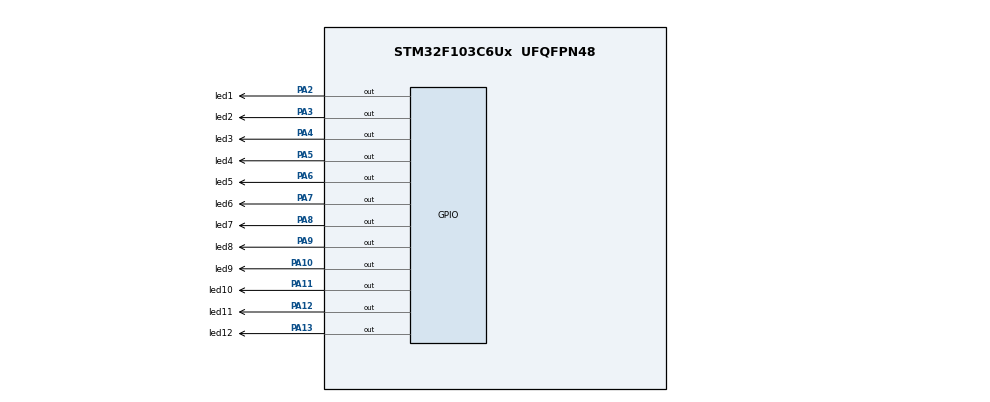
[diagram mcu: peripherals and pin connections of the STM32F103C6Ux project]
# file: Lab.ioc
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Mcu.Family=STM32F1
Mcu.Name=STM32F103C6Ux
Mcu.Package=UFQFPN48
NVIC.PriorityGroup=NVIC_PRIORITYGROUP_4
PA10.GPIO_Label=led9
PA10.Signal=GPIO_Output
PA11.GPIO_Label=led10
PA11.Signal=GPIO_Output
PA12.GPIO_Label=led11
PA12.Signal=GPIO_Output
PA13.GPIO_Label=led12
PA13.Signal=GPIO_Output
PA2.GPIO_Label=led1
PA2.Signal=GPIO_Output
PA3.GPIO_Label=led2
PA3.Signal=GPIO_Output
PA4.GPIO_Label=led3
PA4.Signal=GPIO_Output
PA5.GPIO_Label=led4
PA5.Signal=GPIO_Output
PA6.GPIO_Label=led5
PA6.Signal=GPIO_Output
PA7.GPIO_Label=led6
PA7.Signal=GPIO_Output
PA8.GPIO_Label=led7
PA8.Signal=GPIO_Output
PA9.GPIO_Label=led8
PA9.Signal=GPIO_Output
ProjectManager.HeapSize=0x200
ProjectManager.StackSize=0x400
ProjectManager.TargetToolchain=STM32CubeIDE
RCC.APB1Freq_Value=8000000
RCC.APB2Freq_Value=8000000
VP_SYS_VS_ND.Mode=No_Debug
board=custom

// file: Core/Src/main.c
/* USER CODE BEGIN Header */
/**
  ******************************************************************************
  * @file           : main.c
  * @brief          : Main program body
  ******************************************************************************
  * @attention
  *
  * <h2><center>&copy; Copyright (c) 2022 STMicroelectronics.
  * All rights reserved.</center></h2>
  *
  * This software component is licensed by ST under BSD 3-Clause license,
  * the "License"; You may not use this file except in compliance with the
  * License. You may obtain a copy of the License at:
  *                        opensource.org/licenses/BSD-3-Clause
  *
  ******************************************************************************
  */
/* USER CODE END Header */
#include "main.h"

void SystemClock_Config(void);
static void MX_GPIO_Init(void);

int main(void)
{

  /* MCU Configuration--------------------------------------------------------*/

  /* Reset of all peripherals, Initializes the Flash interface and the Systick. */
  HAL_Init();

  /* Configure the system clock */
  SystemClock_Config();

  /* Initialize all configured peripherals */
  MX_GPIO_Init();

  /* Infinite loop */
  /* USER CODE BEGIN WHILE */
  while (1)
  {
	  HAL_GPIO_WritePin (green1_GPIO_Port , green1_Pin, GPIO_PIN_RESET);
	  HAL_GPIO_WritePin (yellow1_GPIO_Port , yellow1_Pin, GPIO_PIN_RESET);
	  HAL_GPIO_WritePin (green2_GPIO_Port , green2_Pin, GPIO_PIN_SET); //Green 2 on
	  HAL_GPIO_WritePin (yellow2_GPIO_Port , yellow2_Pin, GPIO_PIN_RESET);
	  HAL_GPIO_WritePin (green3_GPIO_Port , green3_Pin, GPIO_PIN_RESET);
	  HAL_GPIO_WritePin (yellow3_GPIO_Port , yellow3_Pin, GPIO_PIN_RESET);
	  HAL_GPIO_WritePin (red2_GPIO_Port , red2_Pin, GPIO_PIN_RESET);
	  HAL_GPIO_WritePin (red4_GPIO_Port , red4_Pin, GPIO_PIN_RESET);
	  HAL_GPIO_WritePin (green4_GPIO_Port , green4_Pin, GPIO_PIN_SET); //Green4 on
	  HAL_GPIO_WritePin (yellow4_GPIO_Port , yellow4_Pin, GPIO_PIN_RESET);
	  HAL_GPIO_WritePin (red1_GPIO_Port , red1_Pin, GPIO_PIN_SET); //red 1 on
	  HAL_GPIO_WritePin (red3_GPIO_Port , red3_Pin, GPIO_PIN_SET); //red 3 on
	  display7SEG(3);
	  HAL_Delay(1000);
	  display7SEG(2);
	  HAL_Delay(1000);
	  display7SEG(1);
	  HAL_Delay(1000);

	  //Next state
	  HAL_GPIO_WritePin (green1_GPIO_Port , green1_Pin, GPIO_PIN_RESET);
	  HAL_GPIO_WritePin (yellow1_GPIO_Port , yellow1_Pin, GPIO_PIN_RESET); //YELLOW1
	  HAL_GPIO_WritePin (green2_GPIO_Port , green2_Pin, GPIO_PIN_RESET);
	  HAL_GPIO_WritePin (yellow2_GPIO_Port , yellow2_Pin, GPIO_PIN_SET); //yellow on
	  HAL_GPIO_WritePin (green3_GPIO_Port , green3_Pin, GPIO_PIN_RESET);
	  HAL_GPIO_WritePin (yellow3_GPIO_Port , yellow3_Pin, GPIO_PIN_RESET); //YELLOW3
	  HAL_GPIO_WritePin (red2_GPIO_Port , red2_Pin, GPIO_PIN_RESET);
	  HAL_GPIO_WritePin (red4_GPIO_Port , red4_Pin, GPIO_PIN_RESET);
	  HAL_GPIO_WritePin (green4_GPIO_Port , green4_Pin, GPIO_PIN_RESET);
	  HAL_GPIO_WritePin (yellow4_GPIO_Port , yellow4_Pin, GPIO_PIN_SET); // yellow on
	  HAL_GPIO_WritePin (red1_GPIO_Port , red1_Pin, GPIO_PIN_SET);
	  HAL_GPIO_WritePin (red3_GPIO_Port , red3_Pin, GPIO_PIN_SET);
	  display7SEG(2);
	  HAL_Delay(1000);
	  display7SEG(1);
	  HAL_Delay(1000);

	  //Next State
	  HAL_GPIO_WritePin (green1_GPIO_Port , green1_Pin, GPIO_PIN_SET); //green 1 on
	  HAL_GPIO_WritePin (yellow1_GPIO_Port , yellow1_Pin, GPIO_PIN_RESET);
	  HAL_GPIO_WritePin (green2_GPIO_Port , green2_Pin, GPIO_PIN_RESET);
	  HAL_GPIO_WritePin (yellow2_GPIO_Port , yellow2_Pin, GPIO_PIN_RESET);
	  HAL_GPIO_WritePin (green3_GPIO_Port , green3_Pin, GPIO_PIN_SET); // green 3 on
	  HAL_GPIO_WritePin (yellow3_GPIO_Port , yellow3_Pin, GPIO_PIN_RESET);
	  HAL_GPIO_WritePin (red2_GPIO_Port , red2_Pin, GPIO_PIN_SET); //red 2 on
	  HAL_GPIO_WritePin (red4_GPIO_Port , red4_Pin, GPIO_PIN_SET);// red 4 on
	  HAL_GPIO_WritePin (green4_GPIO_Port , green4_Pin, GPIO_PIN_RESET);
	  HAL_GPIO_WritePin (yellow4_GPIO_Port , yellow4_Pin, GPIO_PIN_RESET);
	  HAL_GPIO_WritePin (red1_GPIO_Port , red1_Pin, GPIO_PIN_RESET);
	  HAL_GPIO_WritePin (red3_GPIO_Port , red3_Pin, GPIO_PIN_RESET);
	  display7SEG(3);
	  HAL_Delay(1000);
	  display7SEG(2);
	  HAL_Delay(1000);
	  display7SEG(1);
	  HAL_Delay(1000);

	  //FINAL STATE
	  HAL_GPIO_WritePin (green1_GPIO_Port , green1_Pin, GPIO_PIN_RESET);
	  HAL_GPIO_WritePin (yellow1_GPIO_Port , yellow1_Pin, GPIO_PIN_SET); //yellow on
	  HAL_GPIO_WritePin (green2_GPIO_Port , green2_Pin, GPIO_PIN_RESET);
	  HAL_GPIO_WritePin (yellow2_GPIO_Port , yellow2_Pin, GPIO_PIN_RESET); //YELLOW2
	  HAL_GPIO_WritePin (green3_GPIO_Port , green3_Pin, GPIO_PIN_RESET);
	  HAL_GPIO_WritePin (yellow3_GPIO_Port , yellow3_Pin, GPIO_PIN_SET); //yellow on
	  HAL_GPIO_WritePin (red2_GPIO_Port , red2_Pin, GPIO_PIN_SET);
	  HAL_GPIO_WritePin (red4_GPIO_Port , red4_Pin, GPIO_PIN_SET);
	  HAL_GPIO_WritePin (green4_GPIO_Port , green4_Pin, GPIO_PIN_RESET);
	  HAL_GPIO_WritePin (yellow4_GPIO_Port , yellow4_Pin, GPIO_PIN_RESET); //YELLOW4
	  HAL_GPIO_WritePin (red1_GPIO_Port , red1_Pin, GPIO_PIN_RESET);
	  HAL_GPIO_WritePin (red3_GPIO_Port , red3_Pin, GPIO_PIN_RESET);
	  display7SEG(2);
	  HAL_Delay(1000);
	  display7SEG(1);
	  HAL_Delay(1000);

  }
  /* USER CODE END 3 */
}

void SystemClock_Config(void)
{
  RCC_OscInitTypeDef RCC_OscInitStruct = {0};
  RCC_ClkInitTypeDef RCC_ClkInitStruct = {0};

  /** Initializes the RCC Oscillators according to the specified parameters
  * in the RCC_OscInitTypeDef structure.
  */
  RCC_OscInitStruct.OscillatorType = RCC_OSCILLATORTYPE_HSI;
  RCC_OscInitStruct.HSIState = RCC_HSI_ON;
  RCC_OscInitStruct.HSICalibrationValue = RCC_HSICALIBRATION_DEFAULT;
  RCC_OscInitStruct.PLL.PLLState = RCC_PLL_NONE;
  if (HAL_RCC_OscConfig(&RCC_OscInitStruct) != HAL_OK)
  {
    Error_Handler();
  }
  /** Initializes the CPU, AHB and APB buses clocks
  */
  RCC_ClkInitStruct.ClockType = RCC_CLOCKTYPE_HCLK|RCC_CLOCKTYPE_SYSCLK
                              |RCC_CLOCKTYPE_PCLK1|RCC_CLOCKTYPE_PCLK2;
  RCC_ClkInitStruct.SYSCLKSource = RCC_SYSCLKSOURCE_HSI;
  RCC_ClkInitStruct.AHBCLKDivider = RCC_SYSCLK_DIV1;
  RCC_ClkInitStruct.APB1CLKDivider = RCC_HCLK_DIV1;
  RCC_ClkInitStruct.APB2CLKDivider = RCC_HCLK_DIV1;

  if (HAL_RCC_ClockConfig(&RCC_ClkInitStruct, FLASH_LATENCY_0) != HAL_OK)
  {
    Error_Handler();
  }
}

static void MX_GPIO_Init(void)
{
  GPIO_InitTypeDef GPIO_InitStruct = {0};

  /* GPIO Ports Clock Enable */
  __HAL_RCC_GPIOA_CLK_ENABLE();
  __HAL_RCC_GPIOB_CLK_ENABLE();

  /*Configure GPIO pin Output Level */
  HAL_GPIO_WritePin(GPIOA, red1_Pin|green1_Pin|yellow1_Pin|red2_Pin
                          |green2_Pin|yellow2_Pin|red3_Pin|green3_Pin
                          |yellow3_Pin|red4_Pin|green4_Pin|yellow4_Pin, GPIO_PIN_RESET);

  /*Configure GPIO pin Output Level */
  HAL_GPIO_WritePin(GPIOB, a_Pin|b_Pin|c_Pin|d_Pin
                          |e_Pin|f_Pin|g_Pin, GPIO_PIN_RESET);

  /*Configure GPIO pins : red1_Pin green1_Pin yellow1_Pin red2_Pin
                           green2_Pin yellow2_Pin red3_Pin green3_Pin
                           yellow3_Pin red4_Pin green4_Pin yellow4_Pin */
  GPIO_InitStruct.Pin = red1_Pin|green1_Pin|yellow1_Pin|red2_Pin
                          |green2_Pin|yellow2_Pin|red3_Pin|green3_Pin
                          |yellow3_Pin|red4_Pin|green4_Pin|yellow4_Pin;
  GPIO_InitStruct.Mode = GPIO_MODE_OUTPUT_PP;
  GPIO_InitStruct.Pull = GPIO_NOPULL;
  GPIO_InitStruct.Speed = GPIO_SPEED_FREQ_LOW;
  HAL_GPIO_Init(GPIOA, &GPIO_InitStruct);

  /*Configure GPIO pins : a_Pin b_Pin c_Pin d_Pin
                           e_Pin f_Pin g_Pin */
  GPIO_InitStruct.Pin = a_Pin|b_Pin|c_Pin|d_Pin
                          |e_Pin|f_Pin|g_Pin;
  GPIO_InitStruct.Mode = GPIO_MODE_OUTPUT_PP;
  GPIO_InitStruct.Pull = GPIO_NOPULL;
  GPIO_InitStruct.Speed = GPIO_SPEED_FREQ_LOW;
  HAL_GPIO_Init(GPIOB, &GPIO_InitStruct);

}

/* USER CODE BEGIN 4 */
void display7SEG(int counter){
	if(counter == 0){
		HAL_GPIO_WritePin (a_GPIO_Port, a_Pin, GPIO_PIN_RESET);
		HAL_GPIO_WritePin (b_GPIO_Port, b_Pin, GPIO_PIN_RESET);
		HAL_GPIO_WritePin (c_GPIO_Port, c_Pin, GPIO_PIN_RESET);
		HAL_GPIO_WritePin (d_GPIO_Port, d_Pin, GPIO_PIN_RESET);
		HAL_GPIO_WritePin (e_GPIO_Port, e_Pin, GPIO_PIN_RESET);
		HAL_GPIO_WritePin (f_GPIO_Port, f_Pin, GPIO_PIN_RESET);
		HAL_GPIO_WritePin (g_GPIO_Port, g_Pin, GPIO_PIN_SET);
	}
	else if(counter == 1){
		HAL_GPIO_WritePin (a_GPIO_Port, a_Pin, GPIO_PIN_SET);
		HAL_GPIO_WritePin (b_GPIO_Port, b_Pin, GPIO_PIN_RESET);
		HAL_GPIO_WritePin (c_GPIO_Port, c_Pin, GPIO_PIN_RESET);
		HAL_GPIO_WritePin (d_GPIO_Port, d_Pin, GPIO_PIN_SET);
		HAL_GPIO_WritePin (e_GPIO_Port, e_Pin, GPIO_PIN_SET);
		HAL_GPIO_WritePin (f_GPIO_Port, f_Pin, GPIO_PIN_SET);
		HAL_GPIO_WritePin (g_GPIO_Port, g_Pin, GPIO_PIN_SET);
	}
	else if (counter == 2){
		HAL_GPIO_WritePin (a_GPIO_Port, a_Pin, GPIO_PIN_RESET);
		HAL_GPIO_WritePin (b_GPIO_Port, b_Pin, GPIO_PIN_RESET);
		HAL_GPIO_WritePin (c_GPIO_Port, c_Pin, GPIO_PIN_SET);
		HAL_GPIO_WritePin (d_GPIO_Port, d_Pin, GPIO_PIN_RESET);
		HAL_GPIO_WritePin (e_GPIO_Port, e_Pin, GPIO_PIN_RESET);
		HAL_GPIO_WritePin (f_GPIO_Port, f_Pin, GPIO_PIN_SET);
		HAL_GPIO_WritePin (g_GPIO_Port, g_Pin, GPIO_PIN_RESET);
	}
	else if (counter == 3){
		HAL_GPIO_WritePin (a_GPIO_Port, a_Pin, GPIO_PIN_RESET);
		HAL_GPIO_WritePin (b_GPIO_Port, b_Pin, GPIO_PIN_RESET);
		HAL_GPIO_WritePin (c_GPIO_Port, c_Pin, GPIO_PIN_RESET);
		HAL_GPIO_WritePin (d_GPIO_Port, d_Pin, GPIO_PIN_RESET);
		HAL_GPIO_WritePin (e_GPIO_Port, e_Pin, GPIO_PIN_SET);
		HAL_GPIO_WritePin (f_GPIO_Port, f_Pin, GPIO_PIN_SET);
		HAL_GPIO_WritePin (g_GPIO_Port, g_Pin, GPIO_PIN_RESET);
	}
	else if (counter == 4){
		HAL_GPIO_WritePin (a_GPIO_Port, a_Pin, GPIO_PIN_SET);
		HAL_GPIO_WritePin (b_GPIO_Port, b_Pin, GPIO_PIN_RESET);
		HAL_GPIO_WritePin (c_GPIO_Port, c_Pin, GPIO_PIN_RESET);
		HAL_GPIO_WritePin (d_GPIO_Port, d_Pin, GPIO_PIN_SET);
		HAL_GPIO_WritePin (e_GPIO_Port, e_Pin, GPIO_PIN_SET);
		HAL_GPIO_WritePin (f_GPIO_Port, f_Pin, GPIO_PIN_RESET);
		HAL_GPIO_WritePin (g_GPIO_Port, g_Pin, GPIO_PIN_RESET);
	}
	else if (counter == 5){
		HAL_GPIO_WritePin (a_GPIO_Port, a_Pin, GPIO_PIN_RESET);
		HAL_GPIO_WritePin (b_GPIO_Port, b_Pin, GPIO_PIN_SET);
		HAL_GPIO_WritePin (c_GPIO_Port, c_Pin, GPIO_PIN_RESET);
		HAL_GPIO_WritePin (d_GPIO_Port, d_Pin, GPIO_PIN_RESET);
		HAL_GPIO_WritePin (e_GPIO_Port, e_Pin, GPIO_PIN_SET);
		HAL_GPIO_WritePin (f_GPIO_Port, f_Pin, GPIO_PIN_RESET);
		HAL_GPIO_WritePin (g_GPIO_Port, g_Pin, GPIO_PIN_RESET);
	}
	else if (counter == 6){
		HAL_GPIO_WritePin (a_GPIO_Port, a_Pin, GPIO_PIN_RESET);
		HAL_GPIO_WritePin (b_GPIO_Port, b_Pin, GPIO_PIN_SET);
		HAL_GPIO_WritePin (c_GPIO_Port, c_Pin, GPIO_PIN_RESET);
		HAL_GPIO_WritePin (d_GPIO_Port, d_Pin, GPIO_PIN_RESET);
		HAL_GPIO_WritePin (e_GPIO_Port, e_Pin, GPIO_PIN_RESET);
		HAL_GPIO_WritePin (f_GPIO_Port, f_Pin, GPIO_PIN_RESET);
		HAL_GPIO_WritePin (g_GPIO_Port, g_Pin, GPIO_PIN_RESET);
	}
	else if (counter == 7){
		HAL_GPIO_WritePin (a_GPIO_Port, a_Pin, GPIO_PIN_RESET);
		HAL_GPIO_WritePin (b_GPIO_Port, b_Pin, GPIO_PIN_RESET);
		HAL_GPIO_WritePin (c_GPIO_Port, c_Pin, GPIO_PIN_RESET);
		HAL_GPIO_WritePin (d_GPIO_Port, d_Pin, GPIO_PIN_SET);
		HAL_GPIO_WritePin (e_GPIO_Port, e_Pin, GPIO_PIN_SET);
		HAL_GPIO_WritePin (f_GPIO_Port, f_Pin, GPIO_PIN_SET);
		HAL_GPIO_WritePin (g_GPIO_Port, g_Pin, GPIO_PIN_SET);
	}
	else if (counter == 8){
		HAL_GPIO_WritePin (a_GPIO_Port, a_Pin, GPIO_PIN_RESET);
		HAL_GPIO_WritePin (b_GPIO_Port, b_Pin, GPIO_PIN_RESET);
		HAL_GPIO_WritePin (c_GPIO_Port, c_Pin, GPIO_PIN_RESET);
		HAL_GPIO_WritePin (d_GPIO_Port, d_Pin, GPIO_PIN_RESET);
		HAL_GPIO_WritePin (e_GPIO_Port, e_Pin, GPIO_PIN_RESET);
		HAL_GPIO_WritePin (f_GPIO_Port, f_Pin, GPIO_PIN_RESET);
		HAL_GPIO_WritePin (g_GPIO_Port, g_Pin, GPIO_PIN_RESET);
	}
	else if (counter == 9){
		HAL_GPIO_WritePin (a_GPIO_Port, a_Pin, GPIO_PIN_RESET);
		HAL_GPIO_WritePin (b_GPIO_Port, b_Pin, GPIO_PIN_RESET);
		HAL_GPIO_WritePin (c_GPIO_Port, c_Pin, GPIO_PIN_RESET);
		HAL_GPIO_WritePin (d_GPIO_Port, d_Pin, GPIO_PIN_RESET);
		HAL_GPIO_WritePin (e_GPIO_Port, e_Pin, GPIO_PIN_SET);
		HAL_GPIO_WritePin (f_GPIO_Port, f_Pin, GPIO_PIN_RESET);
		HAL_GPIO_WritePin (g_GPIO_Port, g_Pin, GPIO_PIN_RESET);
	}
}
/* USER CODE END 4 */

void Error_Handler(void)
{
  __disable_irq();
  while (1)
  {
  }
}

/************************ (C) COPYRIGHT STMicroelectronics *****END OF FILE****/
